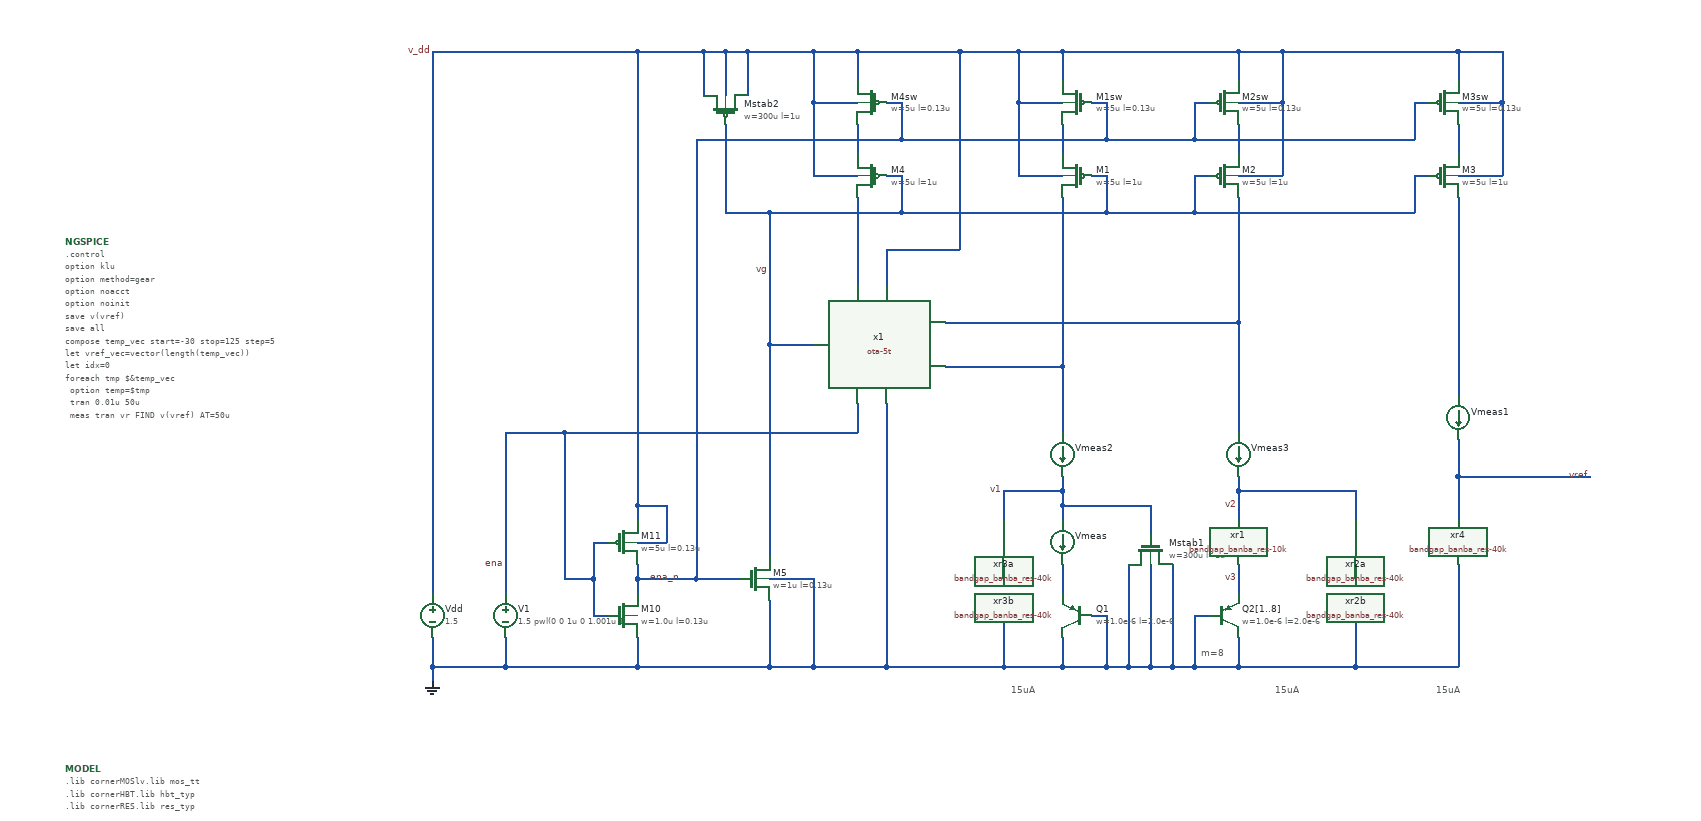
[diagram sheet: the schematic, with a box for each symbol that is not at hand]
v {xschem version=3.4.6 file_version=1.2}
G {}
K {}
V {}
S {}
E {}
T {m=8} 1550 -330 0 0 0.4 0.4 {}
T {15uA} 1290 -280 0 0 0.4 0.4 {}
T {15uA} 1650 -280 0 0 0.4 0.4 {}
T {15uA} 1870 -280 0 0 0.4 0.4 {}
N 500 -300 500 -280 {
lab=GND}
N 500 -340 500 -300 {
lab=GND}
N 1600 -340 1600 -300 {lab=GND}
N 1360 -340 1360 -300 {lab=GND}
N 1540 -370 1560 -370 {lab=GND}
N 1540 -370 1540 -300 {lab=GND}
N 1400 -370 1420 -370 {lab=GND}
N 1420 -370 1420 -300 {lab=GND}
N 1360 -300 1420 -300 {
lab=GND}
N 1600 -440 1600 -400 {lab=v3}
N 1300 -970 1360 -970 {lab=v_dd}
N 1600 -970 1660 -970 {lab=v_dd}
N 1900 -560 2080 -560 {lab=vref}
N 1360 -440 1360 -400 {lab=#net1}
N 1540 -300 1600 -300 {lab=GND}
N 1020 -970 1080 -970 {lab=v_dd}
N 960 -740 1020 -740 {lab=vg}
N 1900 -970 1960 -970 {lab=v_dd}
N 1840 -970 1860 -970 {lab=vg}
N 1840 -970 1840 -920 {lab=vg}
N 1280 -540 1280 -500 {lab=v1}
N 1280 -540 1360 -540 {lab=v1}
N 1280 -300 1360 -300 {
lab=GND}
N 1600 -540 1760 -540 {lab=v2}
N 1760 -540 1760 -500 {lab=v2}
N 1760 -300 1900 -300 {lab=GND}
N 1120 -660 1120 -300 {lab=GND}
N 1120 -870 1220 -870 {lab=v_dd}
N 1120 -870 1120 -820 {lab=v_dd}
N 1900 -940 1900 -670 {lab=#net2}
N 1360 -560 1360 -540 {lab=v1}
N 1600 -540 1600 -500 {lab=v2}
N 1600 -560 1600 -540 {lab=v2}
N 1900 -440 1900 -300 {lab=GND}
N 1900 -560 1900 -500 {lab=vref}
N 1080 -940 1080 -820 {lab=#net3}
N 1200 -710 1360 -710 {lab=#net4}
N 1360 -940 1360 -710 {lab=#net4}
N 1200 -770 1600 -770 {lab=#net5}
N 1600 -940 1600 -770 {lab=#net5}
N 1900 -610 1900 -560 {lab=vref}
N 600 -340 600 -300 {lab=GND}
N 500 -300 600 -300 {
lab=GND}
N 1360 -520 1360 -500 {lab=v1}
N 600 -620 600 -400 {lab=ena}
N 960 -390 960 -300 {lab=GND}
N 780 -300 960 -300 {
lab=GND}
N 960 -740 960 -450 {lab=vg}
N 960 -300 1020 -300 {
lab=GND}
N 1960 -1070 1960 -970 {lab=v_dd}
N 1900 -1140 1960 -1140 {lab=v_dd}
N 1660 -1070 1660 -970 {lab=v_dd}
N 1600 -1140 1660 -1140 {lab=v_dd}
N 1220 -1140 1300 -1140 {lab=v_dd}
N 1080 -1140 1220 -1140 {lab=v_dd}
N 1220 -1140 1220 -870 {lab=v_dd}
N 1020 -1070 1020 -970 {lab=v_dd}
N 500 -1140 500 -400 {lab=v_dd}
N 720 -370 740 -370 {lab=ena}
N 720 -420 720 -370 {lab=ena}
N 720 -470 740 -470 {lab=ena}
N 780 -340 780 -300 {lab=GND}
N 600 -300 780 -300 {
lab=GND}
N 780 -520 780 -500 {lab=v_dd}
N 500 -1140 780 -1140 {lab=v_dd}
N 780 -1140 780 -520 {lab=v_dd}
N 820 -520 820 -470 {lab=v_dd}
N 680 -420 720 -420 {lab=ena}
N 720 -470 720 -420 {lab=ena}
N 680 -620 680 -420 {lab=ena}
N 600 -620 680 -620 {lab=ena}
N 780 -420 780 -400 {lab=ena_n}
N 780 -520 820 -520 {lab=v_dd}
N 780 -470 820 -470 {lab=v_dd}
N 1510 -300 1540 -300 {
lab=GND}
N 1360 -540 1360 -520 {lab=v1}
N 780 -440 780 -420 {lab=ena_n}
N 1360 -710 1360 -620 {lab=#net4}
N 1600 -770 1600 -620 {lab=#net5}
N 1020 -300 1120 -300 {
lab=GND}
N 1080 -660 1080 -620 {lab=ena}
N 960 -420 1020 -420 {lab=GND}
N 1020 -420 1020 -300 {lab=GND}
N 860 -420 920 -420 {lab=ena_n}
N 930 -1140 1020 -1140 {lab=v_dd}
N 960 -920 1140 -920 {lab=vg}
N 960 -920 960 -740 {lab=vg}
N 870 -1140 870 -1080 {lab=v_dd}
N 780 -1140 870 -1140 {lab=v_dd}
N 900 -1140 900 -1080 {lab=v_dd}
N 870 -1140 900 -1140 {lab=v_dd}
N 930 -1140 930 -1080 {lab=v_dd}
N 900 -1140 930 -1140 {lab=v_dd}
N 1360 -520 1480 -520 {lab=v1}
N 1480 -520 1480 -480 {lab=v1}
N 1450 -440 1450 -300 {lab=GND}
N 1420 -300 1450 -300 {
lab=GND}
N 1480 -440 1480 -300 {lab=GND}
N 1450 -300 1480 -300 {
lab=GND}
N 1510 -440 1510 -300 {lab=GND}
N 1480 -300 1510 -300 {
lab=GND}
N 1760 -360 1760 -300 {lab=GND}
N 1600 -300 1760 -300 {lab=GND}
N 1760 -440 1760 -420 {lab=#net6}
N 1280 -360 1280 -300 {lab=GND}
N 1120 -300 1280 -300 {
lab=GND}
N 1280 -440 1280 -420 {lab=#net7}
N 1900 -1140 1900 -1100 {lab=v_dd}
N 1660 -1140 1900 -1140 {lab=v_dd}
N 1900 -1040 1900 -1000 {lab=#net8}
N 1900 -1070 1960 -1070 {lab=v_dd}
N 1960 -1140 1960 -1070 {lab=v_dd}
N 1600 -1040 1600 -1000 {lab=#net9}
N 1600 -1070 1660 -1070 {lab=v_dd}
N 1660 -1140 1660 -1070 {lab=v_dd}
N 1600 -1140 1600 -1100 {lab=v_dd}
N 1360 -1140 1600 -1140 {lab=v_dd}
N 1360 -1140 1360 -1100 {lab=v_dd}
N 1300 -1140 1360 -1140 {lab=v_dd}
N 1300 -1070 1360 -1070 {lab=v_dd}
N 1300 -1070 1300 -970 {lab=v_dd}
N 1360 -1040 1360 -1000 {lab=#net10}
N 1080 -1040 1080 -1000 {lab=#net11}
N 1080 -1140 1080 -1100 {lab=v_dd}
N 1020 -1140 1080 -1140 {lab=v_dd}
N 1020 -1070 1080 -1070 {lab=v_dd}
N 1020 -1140 1020 -1070 {lab=v_dd}
N 1300 -1140 1300 -1070 {lab=v_dd}
N 1840 -1070 1860 -1070 {lab=ena_n}
N 1840 -1070 1840 -1020 {lab=ena_n}
N 1540 -1020 1840 -1020 {lab=ena_n}
N 680 -620 1080 -620 {lab=ena}
N 860 -1020 860 -420 {lab=ena_n}
N 780 -420 860 -420 {lab=ena_n}
N 1120 -1070 1140 -1070 {lab=ena_n}
N 1140 -1070 1140 -1020 {lab=ena_n}
N 860 -1020 1140 -1020 {lab=ena_n}
N 1400 -1070 1420 -1070 {lab=ena_n}
N 1420 -1070 1420 -1020 {lab=ena_n}
N 1140 -1020 1420 -1020 {lab=ena_n}
N 1540 -1070 1560 -1070 {lab=ena_n}
N 1540 -1070 1540 -1020 {lab=ena_n}
N 1420 -1020 1540 -1020 {lab=ena_n}
N 1120 -970 1140 -970 {lab=vg}
N 1400 -970 1420 -970 {lab=vg}
N 1140 -920 1420 -920 {lab=vg}
N 1540 -970 1560 -970 {lab=vg}
N 1540 -970 1540 -920 {lab=vg}
N 1540 -920 1840 -920 {lab=vg}
N 1140 -970 1140 -920 {lab=vg}
N 1420 -970 1420 -920 {lab=vg}
N 900 -1040 900 -920 {lab=vg}
N 900 -920 960 -920 {lab=vg}
N 1420 -920 1540 -920 {lab=vg}
C {devices/code_shown.sym} 0 -160 0 0 {name=MODEL only_toplevel=true
format="tcleval( @value )"
value="
.lib cornerMOSlv.lib mos_tt
.lib cornerHBT.lib hbt_typ
.lib cornerRES.lib res_typ
"}
C {devices/code_shown.sym} 0 -880 0 0 {name=NGSPICE only_toplevel=true 
value="
.control
option klu
option method=gear
option noacct
option noinit
save v(vref)
save all

compose temp_vec start=-30 stop=125 step=5
let vref_vec=vector(length(temp_vec))
let idx=0

foreach tmp $&temp_vec
  option temp=$tmp
  tran 0.01u 50u
  meas tran vr FIND v(vref) AT=50u
  let vref_vec[idx]=vr
  let idx=idx+1
end

plot vref_vec vs temp_vec
wrdata bandgap_banba.txt vref_vec vs temp_vec
.endc
"}
C {devices/vsource.sym} 500 -370 0 0 {name=Vdd value=1.5 savecurrent=true}
C {devices/gnd.sym} 500 -280 0 0 {name=l3 lab=GND}
C {devices/title.sym} 160 -30 0 0 {name=l5 author="(c) 2025 H. Pretl, Apache-2.0 license"}
C {devices/launcher.sym} 480 -150 0 0 {name=h2
descr="simulate" 
tclcommand="xschem save; xschem netlist; xschem simulate"
}
C {devices/launcher.sym} 740 -150 0 0 {name=h3
descr="annotate OP" 
tclcommand="set show_hidden_texts 1; xschem annotate_op"
}
C {lab_pin.sym} 500 -1140 0 0 {name=p2 sig_type=std_logic lab=v_dd}
C {sg13g2_pr/pnpMPA.sym} 1380 -370 0 1 {name=Q1
model=pnpMPA
spiceprefix=X
w=1.0e-6
l=2.0e-6
m=1
}
C {sg13g2_pr/pnpMPA.sym} 1580 -370 0 0 {name=Q2[1..8]
model=pnpMPA
spiceprefix=X
w=1.0e-6
l=2.0e-6
m=1
}
C {lab_wire.sym} 2080 -560 0 0 {name=p1 sig_type=std_logic lab=vref}
C {ammeter.sym} 1360 -470 0 0 {name=Vmeas savecurrent=true spice_ignore=0}
C {ammeter.sym} 1900 -640 0 0 {name=Vmeas1 savecurrent=true spice_ignore=0}
C {lab_pin.sym} 1600 -520 0 0 {name=p3 sig_type=std_logic lab=v2}
C {lab_pin.sym} 1600 -420 0 0 {name=p4 sig_type=std_logic lab=v3}
C {ota-5t.sym} 1120 -740 0 1 {name=x1}
C {sg13g2_pr/sg13_lv_pmos.sym} 1100 -970 0 1 {name=M4
l=1u
w=5u
ng=1
m=1
model=sg13_lv_pmos
spiceprefix=X
}
C {ammeter.sym} 1360 -590 0 0 {name=Vmeas2 savecurrent=true spice_ignore=0}
C {ammeter.sym} 1600 -590 0 0 {name=Vmeas3 savecurrent=true spice_ignore=0}
C {lab_pin.sym} 1280 -540 0 0 {name=p5 sig_type=std_logic lab=v1}
C {sg13g2_pr/sg13_lv_pmos.sym} 1380 -970 0 1 {name=M1
l=1u
w=5u
ng=1
m=1
model=sg13_lv_pmos
spiceprefix=X
}
C {sg13g2_pr/sg13_lv_pmos.sym} 1580 -970 0 0 {name=M2
l=1u
w=5u
ng=1
m=1
model=sg13_lv_pmos
spiceprefix=X
}
C {sg13g2_pr/sg13_lv_pmos.sym} 1880 -970 0 0 {name=M3
l=1u
w=5u
ng=1
m=1
model=sg13_lv_pmos
spiceprefix=X
}
C {lab_pin.sym} 960 -840 0 0 {name=p6 sig_type=std_logic lab=vg}
C {vsource.sym} 600 -370 0 0 {name=V1 value="1.5 pwl(0 0 1u 0 1.001u 1.5)" savecurrent=false}
C {lab_pin.sym} 600 -440 0 0 {name=p7 sig_type=std_logic lab=ena}
C {sg13g2_pr/sg13_lv_nmos.sym} 940 -420 2 1 {name=M5
l=0.13u
w=1u
ng=1
m=1
model=sg13_lv_nmos
spiceprefix=X
}
C {sg13g2_pr/sg13_lv_nmos.sym} 760 -370 2 1 {name=M10
l=0.13u
w=1.0u
ng=1
m=1
model=sg13_lv_nmos
spiceprefix=X
}
C {sg13g2_pr/sg13_lv_pmos.sym} 760 -470 0 0 {name=M11
l=0.13u
w=5u
ng=1
m=1
model=sg13_lv_pmos
spiceprefix=X
}
C {sg13g2_pr/sg13_lv_pmos.sym} 900 -1060 1 1 {name=Mstab2
l=1u
w=300u
ng=60
m=1
model=sg13_lv_pmos
spiceprefix=X
}
C {sg13g2_pr/sg13_lv_nmos.sym} 1480 -460 3 1 {name=Mstab1
l=1u
w=300u
ng=60
m=1
model=sg13_lv_nmos
spiceprefix=X
}
C {lab_wire.sym} 840 -420 0 0 {name=p8 sig_type=std_logic lab=ena_n}
C {bandgap_banba_res-10k.sym} 1600 -440 0 0 {name=xr1}
C {bandgap_banba_res-40k.sym} 1760 -440 0 0 {name=xr2a}
C {bandgap_banba_res-40k.sym} 1760 -360 0 0 {name=xr2b}
C {bandgap_banba_res-40k.sym} 1280 -440 0 1 {name=xr3a}
C {bandgap_banba_res-40k.sym} 1280 -360 0 1 {name=xr3b}
C {bandgap_banba_res-40k.sym} 1900 -440 0 0 {name=xr4}
C {sg13g2_pr/sg13_lv_pmos.sym} 1880 -1070 0 0 {name=M3sw
l=0.13u
w=5u
ng=1
m=1
model=sg13_lv_pmos
spiceprefix=X
}
C {sg13g2_pr/sg13_lv_pmos.sym} 1580 -1070 0 0 {name=M2sw
l=0.13u
w=5u
ng=1
m=1
model=sg13_lv_pmos
spiceprefix=X
}
C {sg13g2_pr/sg13_lv_pmos.sym} 1380 -1070 0 1 {name=M1sw
l=0.13u
w=5u
ng=1
m=1
model=sg13_lv_pmos
spiceprefix=X
}
C {sg13g2_pr/sg13_lv_pmos.sym} 1100 -1070 0 1 {name=M4sw
l=0.13u
w=5u
ng=1
m=1
model=sg13_lv_pmos
spiceprefix=X
}
